###############################################################
#  Generated by:      Cadence Innovus 20.13-s083_1
#  OS:                Linux x86_64(Host ID rice-503-20-north)
#  Generated on:      Fri Apr 29 22:32:43 2022
#  Design:            inverter
#  Command:           write_lef_abstract -5.8 -extractBlockObs /home/users/lyt1314/ee372/aloe-sky130/aloe/outputs/design.lef
###############################################################

VERSION 5.8 ;

BUSBITCHARS "[]" ;
DIVIDERCHAR "/" ;

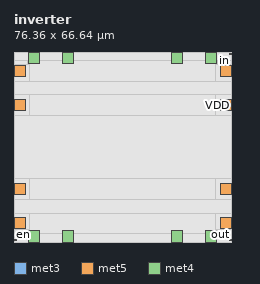
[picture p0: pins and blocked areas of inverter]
MACRO inverter
  CLASS BLOCK ;
  SIZE 76.360000 BY 66.640000 ;
  FOREIGN inverter 0.000000 0.000000 ;
  ORIGIN 0 0 ;
  SYMMETRY X Y R90 ;
  PIN en
    DIRECTION INPUT ;
    USE SIGNAL ;
    PORT
      LAYER met3 ;
        RECT 0.000000 0.520000 0.800000 0.820000 ;
    END
  END en
  PIN in
    DIRECTION INPUT ;
    USE SIGNAL ;
    PORT
      LAYER met3 ;
        RECT 75.560000 65.790000 76.360000 66.090000 ;
    END
  END in
  PIN clk
    DIRECTION INPUT ;
    USE SIGNAL ;
  END clk
  PIN out
    DIRECTION OUTPUT ;
    USE SIGNAL ;
    PORT
      LAYER met3 ;
        RECT 75.560000 0.520000 76.360000 0.820000 ;
    END
  END out
  PIN VDD
    DIRECTION INOUT ;
    USE POWER ;
    PORT
      LAYER met5 ;
        RECT 72.360000 45.960000 76.360000 49.960000 ;
    END
    PORT
      LAYER met5 ;
        RECT 0.000000 45.960000 4.000000 49.960000 ;
    END
    PORT
      LAYER met5 ;
        RECT 72.360000 16.560000 76.360000 20.560000 ;
    END
    PORT
      LAYER met5 ;
        RECT 0.000000 16.560000 4.000000 20.560000 ;
    END
    PORT
      LAYER met4 ;
        RECT 55.110000 62.640000 59.110000 66.640000 ;
    END
    PORT
      LAYER met4 ;
        RECT 55.110000 0.000000 59.110000 4.000000 ;
    END
    PORT
      LAYER met4 ;
        RECT 16.980000 62.640000 20.980000 66.640000 ;
    END
    PORT
      LAYER met4 ;
        RECT 16.980000 0.000000 20.980000 4.000000 ;
    END
  END VDD
  PIN VSS
    DIRECTION INOUT ;
    USE GROUND ;
    PORT
      LAYER met5 ;
        RECT 72.360000 57.960000 76.360000 61.960000 ;
    END
    PORT
      LAYER met5 ;
        RECT 0.000000 57.960000 4.000000 61.960000 ;
    END
    PORT
      LAYER met5 ;
        RECT 72.360000 4.560000 76.360000 8.560000 ;
    END
    PORT
      LAYER met5 ;
        RECT 0.000000 4.560000 4.000000 8.560000 ;
    END
    PORT
      LAYER met4 ;
        RECT 67.110000 62.640000 71.110000 66.640000 ;
    END
    PORT
      LAYER met4 ;
        RECT 67.110000 0.000000 71.110000 4.000000 ;
    END
    PORT
      LAYER met4 ;
        RECT 4.980000 62.640000 8.980000 66.640000 ;
    END
    PORT
      LAYER met4 ;
        RECT 4.980000 0.000000 8.980000 4.000000 ;
    END
  END VSS
  OBS
    LAYER li1 ;
      RECT 0.000000 0.000000 76.360000 66.640000 ;
    LAYER met1 ;
      RECT 0.000000 0.000000 76.360000 66.640000 ;
    LAYER met2 ;
      RECT 0.000000 0.000000 76.360000 66.640000 ;
    LAYER met3 ;
      RECT 0.000000 66.490000 76.360000 66.640000 ;
      RECT 0.000000 65.390000 75.160000 66.490000 ;
      RECT 0.000000 1.220000 76.360000 65.390000 ;
      RECT 1.200000 0.120000 75.160000 1.220000 ;
      RECT 0.000000 0.000000 76.360000 0.120000 ;
    LAYER met4 ;
      RECT 71.510000 62.240000 76.360000 66.640000 ;
      RECT 59.510000 62.240000 66.710000 66.640000 ;
      RECT 21.380000 62.240000 54.710000 66.640000 ;
      RECT 9.380000 62.240000 16.580000 66.640000 ;
      RECT 0.000000 62.240000 4.580000 66.640000 ;
      RECT 0.000000 4.400000 76.360000 62.240000 ;
      RECT 71.510000 0.000000 76.360000 4.400000 ;
      RECT 59.510000 0.000000 66.710000 4.400000 ;
      RECT 21.380000 0.000000 54.710000 4.400000 ;
      RECT 9.380000 0.000000 16.580000 4.400000 ;
      RECT 0.000000 0.000000 4.580000 4.400000 ;
    LAYER met5 ;
      RECT 0.000000 63.560000 76.360000 66.640000 ;
      RECT 5.600000 56.360000 70.760000 63.560000 ;
      RECT 0.000000 51.560000 76.360000 56.360000 ;
      RECT 5.600000 44.360000 70.760000 51.560000 ;
      RECT 0.000000 22.160000 76.360000 44.360000 ;
      RECT 5.600000 14.960000 70.760000 22.160000 ;
      RECT 0.000000 10.160000 76.360000 14.960000 ;
      RECT 5.600000 2.960000 70.760000 10.160000 ;
      RECT 0.000000 0.000000 76.360000 2.960000 ;
  END
END inverter

END LIBRARY
